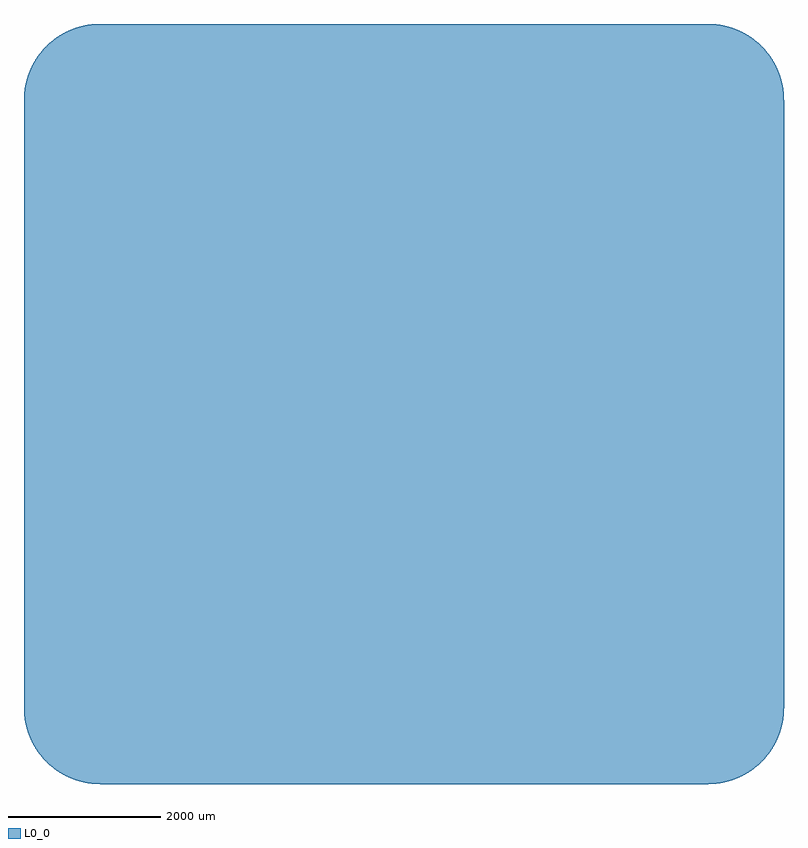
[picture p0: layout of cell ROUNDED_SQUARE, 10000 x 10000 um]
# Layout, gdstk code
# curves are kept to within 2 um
import gdstk
lib = gdstk.Library(unit=1e-6, precision=1e-09)
def R(c, l, rs):  # rectangles x0, y0, x1, y1
    for r in rs: c.add(gdstk.rectangle(r[:2], r[2:], *l))
def P(c, l, *ps):  # polygons
    for p in ps: c.add(gdstk.Polygon(p, *l))
L0_0 = (0, 0)

rounded_square = lib.new_cell('ROUNDED_SQUARE')
R(rounded_square, L0_0, [(-4000,-5000,4000,5000), (-4000,-5000,4000,5000), (-5000,-4000,-4000,4000), (4000,-4000,5000,4000)])
P(rounded_square, L0_0, [(-4000,-4000),(-5000,-4000),(-4992.115,-4125.333),(-4980.566,-4196.191),(-4966.312,-4257.374),(-4926.435,-4376.455),(-4900.969,-4433.884),(-4867.518,-4497.407),(-4829.595,-4558.366),(-4792.898,-4609.355),(-4710.273,-4703.926),(-4664.672,-4747.136),(-4609.355,-4792.898),(-4558.366,-4829.595),(-4497.407,-4867.518),(-4433.884,-4900.969),(-4376.455,-4926.435),(-4257.374,-4966.312),(-4196.191,-4980.566),(-4125.333,-4992.115),(-4000,-5000)],
  [(4000,-4000),(4000,-5000),(4125.333,-4992.115),(4196.191,-4980.566),(4257.374,-4966.312),(4376.455,-4926.435),(4433.884,-4900.969),(4497.407,-4867.518),(4558.366,-4829.595),(4609.355,-4792.898),(4703.926,-4710.273),(4747.136,-4664.672),(4792.898,-4609.355),(4829.595,-4558.366),(4867.518,-4497.407),(4900.969,-4433.884),(4926.435,-4376.455),(4966.312,-4257.374),(4980.566,-4196.191),(4992.115,-4125.333),(5000,-4000)],
  [(4000,4000),(5000,4000),(4992.115,4125.333),(4980.566,4196.191),(4966.312,4257.374),(4926.435,4376.455),(4900.969,4433.884),(4867.518,4497.407),(4829.595,4558.366),(4792.898,4609.355),(4710.273,4703.926),(4664.672,4747.136),(4609.355,4792.898),(4558.366,4829.595),(4497.407,4867.518),(4433.884,4900.969),(4376.455,4926.435),(4257.374,4966.312),(4196.191,4980.566),(4125.333,4992.115),(4000,5000)],
  [(-4000,4000),(-4000,5000),(-4125.333,4992.115),(-4196.191,4980.566),(-4257.374,4966.312),(-4376.455,4926.435),(-4433.884,4900.969),(-4497.407,4867.518),(-4558.366,4829.595),(-4609.355,4792.898),(-4703.926,4710.273),(-4747.136,4664.672),(-4792.898,4609.355),(-4829.595,4558.366),(-4867.518,4497.407),(-4900.969,4433.884),(-4926.435,4376.455),(-4966.312,4257.374),(-4980.566,4196.191),(-4992.115,4125.333),(-5000,4000)])

lib.write_gds('ROUNDED_SQUARE.gds')
